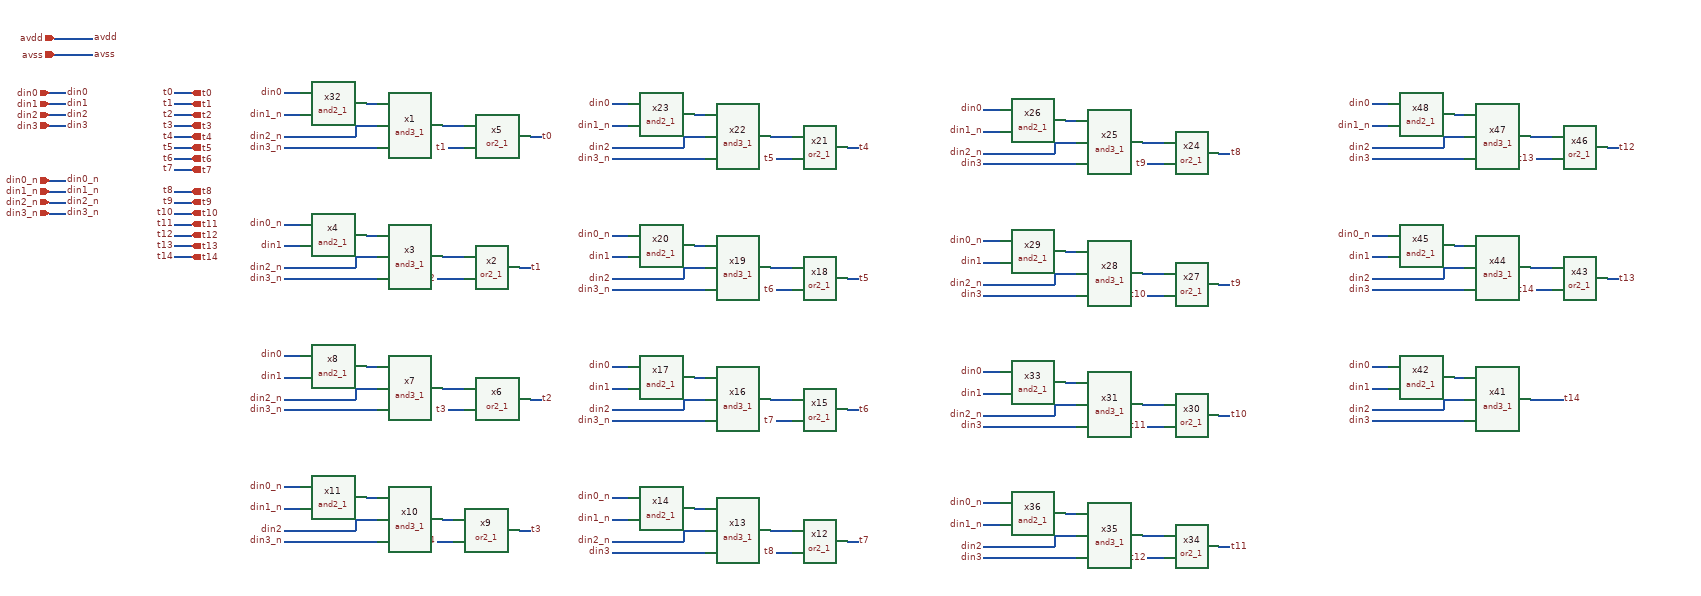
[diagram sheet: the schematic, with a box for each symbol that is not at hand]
v {xschem version=3.4.5 file_version=1.2
}
G {}
K {}
V {}
S {}
E {}
N -50 -70 -20 -70 {
lab=din0}
N -50 -50 -20 -50 {
lab=din1}
N -50 -30 -20 -30 {
lab=din2}
N -50 -10 -20 -10 {
lab=din3}
N -50 90 -20 90 {
lab=din0_n}
N -50 110 -20 110 {
lab=din1_n}
N -50 130 -20 130 {
lab=din2_n}
N -50 150 -20 150 {
lab=din3_n}
N 180 -70 210 -70 {
lab=t0}
N 180 -50 210 -50 {
lab=t1}
N 180 -30 210 -30 {
lab=t2}
N 180 -10 210 -10 {
lab=t3}
N 180 10 210 10 {
lab=t4}
N 180 30 210 30 {
lab=t5}
N 180 50 210 50 {
lab=t6}
N 180 70 210 70 {
lab=t7}
N 180 110 210 110 {
lab=t8}
N 180 130 210 130 {
lab=t9}
N 180 150 210 150 {
lab=t10}
N 180 170 210 170 {
lab=t11}
N 180 190 210 190 {
lab=t12}
N 180 210 210 210 {
lab=t13}
N 180 230 210 230 {
lab=t14}
N -40 -170 30 -170 {
lab=avdd}
N -40 -140 30 -140 {
lab=avss}
N 380 30 410 30 {
lab=din3_n}
N 380 10 410 10 {
lab=din2_n}
N 380 -30 410 -30 {
lab=din1_n}
N 380 -70 410 -70 {
lab=din0}
N 830 10 850 10 {
lab=t0}
N 670 -10 690 -10 {
lab=#net1}
N 680 30 710 30 {
lab=t1}
N 380 270 410 270 {
lab=din3_n}
N 380 250 410 250 {
lab=din2_n}
N 380 210 410 210 {
lab=din1}
N 380 170 410 170 {
lab=din0_n}
N 810 250 830 250 {
lab=t1}
N 660 270 690 270 {
lab=t2}
N 380 510 410 510 {
lab=din3_n}
N 380 490 410 490 {
lab=din2_n}
N 380 450 410 450 {
lab=din1}
N 380 410 410 410 {
lab=din0}
N 830 490 850 490 {
lab=t2}
N 690 470 710 470 {
lab=#net2}
N 680 510 710 510 {
lab=t3}
N 380 750 410 750 {
lab=din3_n}
N 380 730 410 730 {
lab=din2}
N 380 690 410 690 {
lab=din1_n}
N 380 650 410 650 {
lab=din0_n}
N 810 730 830 730 {
lab=t3}
N 670 710 690 710 {
lab=#net3}
N 660 750 690 750 {
lab=t4}
N 980 50 1010 50 {
lab=din3_n}
N 980 30 1010 30 {
lab=din2}
N 980 -10 1010 -10 {
lab=din1_n}
N 980 -50 1010 -50 {
lab=din0}
N 1410 30 1430 30 {
lab=t4}
N 1290 10 1310 10 {
lab=#net4}
N 1280 50 1310 50 {
lab=t5}
N 980 290 1010 290 {
lab=din3_n}
N 980 270 1010 270 {
lab=din2}
N 980 230 1010 230 {
lab=din1}
N 980 190 1010 190 {
lab=din0_n}
N 1410 270 1430 270 {
lab=t5}
N 1290 250 1310 250 {
lab=#net5}
N 1280 290 1310 290 {
lab=t6}
N 980 530 1010 530 {
lab=din3_n}
N 980 510 1010 510 {
lab=din2}
N 980 470 1010 470 {
lab=din1}
N 980 430 1010 430 {
lab=din0}
N 1410 510 1430 510 {
lab=t6}
N 1290 490 1310 490 {
lab=#net6}
N 1280 530 1310 530 {
lab=t7}
N 980 770 1010 770 {
lab=din3}
N 980 750 1010 750 {
lab=din2_n}
N 980 710 1010 710 {
lab=din1_n}
N 980 670 1010 670 {
lab=din0_n}
N 1410 750 1430 750 {
lab=t7}
N 1290 730 1310 730 {
lab=#net7}
N 1280 770 1310 770 {
lab=t8}
N 1660 60 1690 60 {
lab=din3}
N 1660 40 1690 40 {
lab=din2_n}
N 1660 0 1690 0 {
lab=din1_n}
N 1660 -40 1690 -40 {
lab=din0}
N 2090 40 2110 40 {
lab=t8}
N 1970 20 1990 20 {
lab=#net8}
N 1960 60 1990 60 {
lab=t9}
N 1660 300 1690 300 {
lab=din3}
N 1660 280 1690 280 {
lab=din2_n}
N 1660 240 1690 240 {
lab=din1}
N 1660 200 1690 200 {
lab=din0_n}
N 2090 280 2110 280 {
lab=t9}
N 1970 260 1990 260 {
lab=#net9}
N 1960 300 1990 300 {
lab=t10}
N 1660 540 1690 540 {
lab=din3}
N 1660 520 1690 520 {
lab=din2_n}
N 1660 480 1690 480 {
lab=din1}
N 1660 440 1690 440 {
lab=din0}
N 2090 520 2110 520 {
lab=t10}
N 1970 500 1990 500 {
lab=#net10}
N 1960 540 1990 540 {
lab=t11}
N 1660 780 1690 780 {
lab=din3}
N 1660 760 1690 760 {
lab=din2}
N 1660 720 1690 720 {
lab=din1_n}
N 1660 680 1690 680 {
lab=din0_n}
N 2090 760 2110 760 {
lab=t11}
N 1970 740 1990 740 {
lab=#net11}
N 1960 780 1990 780 {
lab=t12}
N 2370 50 2400 50 {
lab=din3}
N 2370 30 2400 30 {
lab=din2}
N 2370 -10 2400 -10 {
lab=din1_n}
N 2370 -50 2400 -50 {
lab=din0}
N 2800 30 2820 30 {
lab=t12}
N 2680 10 2700 10 {
lab=#net12}
N 2670 50 2700 50 {
lab=t13}
N 2370 290 2400 290 {
lab=din3}
N 2370 270 2400 270 {
lab=din2}
N 2370 230 2400 230 {
lab=din1}
N 2370 190 2400 190 {
lab=din0_n}
N 2800 270 2820 270 {
lab=t13}
N 2680 250 2700 250 {
lab=#net13}
N 2670 290 2700 290 {
lab=t14}
N 2370 530 2400 530 {
lab=din3}
N 2370 510 2400 510 {
lab=din2}
N 2370 470 2400 470 {
lab=din1}
N 2370 430 2400 430 {
lab=din0}
N 2700 490 2720 490 {
lab=t14}
N 2680 490 2700 490 {
lab=t14}
N 530 -50 550 -50 {
lab=#net14}
N 510 -10 550 -10 {
lab=din2_n}
N 690 -10 710 -10 {
lab=#net1}
N 510 -10 510 10 {
lab=din2_n}
N 410 10 510 10 {
lab=din2_n}
N 410 30 550 30 {
lab=din3_n}
N 670 230 690 230 {
lab=#net15}
N 530 190 550 190 {
lab=#net16}
N 510 230 550 230 {
lab=din2_n}
N 510 230 510 250 {
lab=din2_n}
N 410 250 510 250 {
lab=din2_n}
N 410 270 550 270 {
lab=din3_n}
N 530 430 550 430 {
lab=#net17}
N 510 470 550 470 {
lab=din2_n}
N 510 470 510 490 {
lab=din2_n}
N 410 490 510 490 {
lab=din2_n}
N 410 510 550 510 {
lab=din3_n}
N 530 670 550 670 {
lab=#net18}
N 510 710 550 710 {
lab=din2}
N 510 710 510 730 {
lab=din2}
N 410 730 510 730 {
lab=din2}
N 410 750 550 750 {
lab=din3_n}
N 1270 730 1290 730 {
lab=#net7}
N 1130 690 1150 690 {
lab=#net19}
N 1110 730 1150 730 {
lab=din2_n}
N 1110 730 1110 750 {
lab=din2_n}
N 1010 750 1110 750 {
lab=din2_n}
N 1010 770 1150 770 {
lab=din3}
N 1270 490 1290 490 {
lab=#net6}
N 1130 450 1150 450 {
lab=#net20}
N 1110 490 1150 490 {
lab=din2}
N 1110 490 1110 510 {
lab=din2}
N 1010 510 1110 510 {
lab=din2}
N 1010 530 1150 530 {
lab=din3_n}
N 1270 250 1290 250 {
lab=#net5}
N 1130 210 1150 210 {
lab=#net21}
N 1110 250 1150 250 {
lab=din2}
N 1110 250 1110 270 {
lab=din2}
N 1010 270 1110 270 {
lab=din2}
N 1010 290 1150 290 {
lab=din3_n}
N 1270 10 1290 10 {
lab=#net4}
N 1130 -30 1150 -30 {
lab=#net22}
N 1110 10 1150 10 {
lab=din2}
N 1110 10 1110 30 {
lab=din2}
N 1010 30 1110 30 {
lab=din2}
N 1010 50 1150 50 {
lab=din3_n}
N 1950 20 1970 20 {
lab=#net8}
N 1810 -20 1830 -20 {
lab=#net23}
N 1790 20 1830 20 {
lab=din2_n}
N 1790 20 1790 40 {
lab=din2_n}
N 1690 40 1790 40 {
lab=din2_n}
N 1690 60 1830 60 {
lab=din3}
N 1950 260 1970 260 {
lab=#net9}
N 1810 220 1830 220 {
lab=#net24}
N 1790 260 1830 260 {
lab=din2_n}
N 1790 260 1790 280 {
lab=din2_n}
N 1690 280 1790 280 {
lab=din2_n}
N 1690 300 1830 300 {
lab=din3}
N 1950 500 1970 500 {
lab=#net10}
N 1810 460 1830 460 {
lab=#net25}
N 1790 500 1830 500 {
lab=din2_n}
N 1790 500 1790 520 {
lab=din2_n}
N 1690 520 1790 520 {
lab=din2_n}
N 1690 540 1830 540 {
lab=din3}
N 1950 740 1970 740 {
lab=#net11}
N 1810 700 1830 700 {
lab=#net26}
N 1790 740 1830 740 {
lab=din2}
N 1790 740 1790 760 {
lab=din2}
N 1690 760 1790 760 {
lab=din2}
N 1690 780 1830 780 {
lab=din3}
N 2660 10 2680 10 {
lab=#net12}
N 2520 -30 2540 -30 {
lab=#net27}
N 2500 10 2540 10 {
lab=din2}
N 2500 10 2500 30 {
lab=din2}
N 2400 30 2500 30 {
lab=din2}
N 2400 50 2540 50 {
lab=din3}
N 2660 250 2680 250 {
lab=#net13}
N 2520 210 2540 210 {
lab=#net28}
N 2500 250 2540 250 {
lab=din2}
N 2500 250 2500 270 {
lab=din2}
N 2400 270 2500 270 {
lab=din2}
N 2400 290 2540 290 {
lab=din3}
N 2660 490 2680 490 {
lab=t14}
N 2520 450 2540 450 {
lab=#net29}
N 2500 490 2540 490 {
lab=din2}
N 2500 490 2500 510 {
lab=din2}
N 2400 510 2500 510 {
lab=din2}
N 2400 530 2540 530 {
lab=din3}
N 670 470 690 470 {
lab=#net2}
N 690 230 710 230 {
lab=#net15}
N 690 270 710 270 {
lab=t2}
C {devices/ipin.sym} -50 -70 0 0 {name=p1 lab=din0}
C {devices/ipin.sym} -50 -50 0 0 {name=p2 lab=din1}
C {devices/ipin.sym} -50 -30 0 0 {name=p3 lab=din2}
C {devices/ipin.sym} -50 -10 0 0 {name=p4 lab=din3}
C {devices/ipin.sym} -50 90 0 0 {name=p7 lab=din0_n}
C {devices/ipin.sym} -50 110 0 0 {name=p8 lab=din1_n}
C {devices/ipin.sym} -50 130 0 0 {name=p9 lab=din2_n}
C {devices/ipin.sym} -50 150 0 0 {name=p10 lab=din3_n}
C {devices/opin.sym} 210 -70 0 0 {name=p13 lab=t0}
C {devices/opin.sym} 210 -50 0 0 {name=p14 lab=t1}
C {devices/opin.sym} 210 -30 0 0 {name=p15 lab=t2}
C {devices/opin.sym} 210 -10 0 0 {name=p16 lab=t3}
C {devices/opin.sym} 210 10 0 0 {name=p17 lab=t4}
C {devices/opin.sym} 210 30 0 0 {name=p18 lab=t5}
C {devices/opin.sym} 210 50 0 0 {name=p19 lab=t6}
C {devices/opin.sym} 210 70 0 0 {name=p20 lab=t7}
C {devices/lab_pin.sym} 180 -70 0 0 {name=p21 sig_type=std_logic lab=t0}
C {devices/lab_pin.sym} 180 -50 0 0 {name=p22 sig_type=std_logic lab=t1}
C {devices/lab_pin.sym} 180 -30 0 0 {name=p23 sig_type=std_logic lab=t2}
C {devices/lab_pin.sym} 180 -10 0 0 {name=p24 sig_type=std_logic lab=t3}
C {devices/lab_pin.sym} 180 10 0 0 {name=p25 sig_type=std_logic lab=t4}
C {devices/lab_pin.sym} 180 30 0 0 {name=p26 sig_type=std_logic lab=t5}
C {devices/lab_pin.sym} 180 50 0 0 {name=p27 sig_type=std_logic lab=t6}
C {devices/lab_pin.sym} 180 70 0 0 {name=p28 sig_type=std_logic lab=t7}
C {devices/lab_pin.sym} -20 -70 0 1 {name=p29 sig_type=std_logic lab=din0}
C {devices/lab_pin.sym} -20 -50 0 1 {name=p30 sig_type=std_logic lab=din1}
C {devices/lab_pin.sym} -20 -30 0 1 {name=p31 sig_type=std_logic lab=din2}
C {devices/lab_pin.sym} -20 -10 0 1 {name=p32 sig_type=std_logic lab=din3}
C {devices/lab_pin.sym} -20 90 0 1 {name=p35 sig_type=std_logic lab=din0_n}
C {devices/lab_pin.sym} -20 110 0 1 {name=p36 sig_type=std_logic lab=din1_n}
C {devices/lab_pin.sym} -20 130 0 1 {name=p37 sig_type=std_logic lab=din2_n}
C {devices/lab_pin.sym} -20 150 0 1 {name=p38 sig_type=std_logic lab=din3_n}
C {devices/opin.sym} 210 110 0 0 {name=p41 lab=t8}
C {devices/opin.sym} 210 130 0 0 {name=p42 lab=t9}
C {devices/opin.sym} 210 150 0 0 {name=p43 lab=t10}
C {devices/opin.sym} 210 170 0 0 {name=p44 lab=t11}
C {devices/opin.sym} 210 190 0 0 {name=p45 lab=t12}
C {devices/opin.sym} 210 210 0 0 {name=p46 lab=t13}
C {devices/opin.sym} 210 230 0 0 {name=p47 lab=t14}
C {devices/lab_pin.sym} 180 110 0 0 {name=p49 sig_type=std_logic lab=t8}
C {devices/lab_pin.sym} 180 130 0 0 {name=p50 sig_type=std_logic lab=t9}
C {devices/lab_pin.sym} 180 150 0 0 {name=p51 sig_type=std_logic lab=t10}
C {devices/lab_pin.sym} 180 170 0 0 {name=p52 sig_type=std_logic lab=t11}
C {devices/lab_pin.sym} 180 190 0 0 {name=p53 sig_type=std_logic lab=t12}
C {devices/lab_pin.sym} 180 210 0 0 {name=p54 sig_type=std_logic lab=t13}
C {devices/lab_pin.sym} 180 230 0 0 {name=p55 sig_type=std_logic lab=t14}
C {devices/lab_pin.sym} 380 -70 0 0 {name=p58 sig_type=std_logic lab=din0}
C {devices/lab_pin.sym} 380 -30 0 0 {name=p59 sig_type=std_logic lab=din1_n}
C {devices/lab_pin.sym} 380 10 0 0 {name=p60 sig_type=std_logic lab=din2_n}
C {devices/lab_pin.sym} 380 30 0 0 {name=p61 sig_type=std_logic lab=din3_n}
C {devices/lab_pin.sym} 380 170 0 0 {name=p65 sig_type=std_logic lab=din0_n}
C {devices/lab_pin.sym} 380 210 0 0 {name=p66 sig_type=std_logic lab=din1}
C {devices/lab_pin.sym} 380 250 0 0 {name=p67 sig_type=std_logic lab=din2_n}
C {devices/lab_pin.sym} 380 270 0 0 {name=p68 sig_type=std_logic lab=din3_n}
C {devices/lab_pin.sym} 380 410 0 0 {name=p72 sig_type=std_logic lab=din0}
C {devices/lab_pin.sym} 380 450 0 0 {name=p73 sig_type=std_logic lab=din1}
C {devices/lab_pin.sym} 380 490 0 0 {name=p74 sig_type=std_logic lab=din2_n}
C {devices/lab_pin.sym} 380 510 0 0 {name=p75 sig_type=std_logic lab=din3_n}
C {devices/lab_pin.sym} 380 650 0 0 {name=p79 sig_type=std_logic lab=din0_n}
C {devices/lab_pin.sym} 380 690 0 0 {name=p80 sig_type=std_logic lab=din1_n}
C {devices/lab_pin.sym} 380 730 0 0 {name=p81 sig_type=std_logic lab=din2}
C {devices/lab_pin.sym} 380 750 0 0 {name=p82 sig_type=std_logic lab=din3_n}
C {devices/lab_pin.sym} 980 -50 0 0 {name=p86 sig_type=std_logic lab=din0}
C {devices/lab_pin.sym} 980 -10 0 0 {name=p87 sig_type=std_logic lab=din1_n}
C {devices/lab_pin.sym} 980 30 0 0 {name=p88 sig_type=std_logic lab=din2}
C {devices/lab_pin.sym} 980 50 0 0 {name=p89 sig_type=std_logic lab=din3_n}
C {devices/lab_pin.sym} 980 190 0 0 {name=p93 sig_type=std_logic lab=din0_n}
C {devices/lab_pin.sym} 980 230 0 0 {name=p94 sig_type=std_logic lab=din1}
C {devices/lab_pin.sym} 980 270 0 0 {name=p95 sig_type=std_logic lab=din2}
C {devices/lab_pin.sym} 980 290 0 0 {name=p96 sig_type=std_logic lab=din3_n}
C {devices/lab_pin.sym} 980 430 0 0 {name=p100 sig_type=std_logic lab=din0}
C {devices/lab_pin.sym} 980 470 0 0 {name=p101 sig_type=std_logic lab=din1}
C {devices/lab_pin.sym} 980 510 0 0 {name=p102 sig_type=std_logic lab=din2}
C {devices/lab_pin.sym} 980 530 0 0 {name=p103 sig_type=std_logic lab=din3_n}
C {devices/lab_pin.sym} 980 670 0 0 {name=p107 sig_type=std_logic lab=din0_n}
C {devices/lab_pin.sym} 980 710 0 0 {name=p108 sig_type=std_logic lab=din1_n}
C {devices/lab_pin.sym} 980 750 0 0 {name=p109 sig_type=std_logic lab=din2_n}
C {devices/lab_pin.sym} 980 770 0 0 {name=p110 sig_type=std_logic lab=din3}
C {devices/lab_pin.sym} 1660 -40 0 0 {name=p114 sig_type=std_logic lab=din0}
C {devices/lab_pin.sym} 1660 0 0 0 {name=p115 sig_type=std_logic lab=din1_n}
C {devices/lab_pin.sym} 1660 40 0 0 {name=p116 sig_type=std_logic lab=din2_n}
C {devices/lab_pin.sym} 1660 60 0 0 {name=p117 sig_type=std_logic lab=din3}
C {devices/lab_pin.sym} 1660 200 0 0 {name=p121 sig_type=std_logic lab=din0_n}
C {devices/lab_pin.sym} 1660 240 0 0 {name=p122 sig_type=std_logic lab=din1}
C {devices/lab_pin.sym} 1660 280 0 0 {name=p123 sig_type=std_logic lab=din2_n}
C {devices/lab_pin.sym} 1660 300 0 0 {name=p124 sig_type=std_logic lab=din3}
C {devices/lab_pin.sym} 1660 440 0 0 {name=p128 sig_type=std_logic lab=din0}
C {devices/lab_pin.sym} 1660 480 0 0 {name=p129 sig_type=std_logic lab=din1}
C {devices/lab_pin.sym} 1660 520 0 0 {name=p130 sig_type=std_logic lab=din2_n}
C {devices/lab_pin.sym} 1660 540 0 0 {name=p131 sig_type=std_logic lab=din3}
C {devices/lab_pin.sym} 1660 680 0 0 {name=p135 sig_type=std_logic lab=din0_n}
C {devices/lab_pin.sym} 1660 720 0 0 {name=p136 sig_type=std_logic lab=din1_n}
C {devices/lab_pin.sym} 1660 760 0 0 {name=p137 sig_type=std_logic lab=din2}
C {devices/lab_pin.sym} 1660 780 0 0 {name=p138 sig_type=std_logic lab=din3}
C {devices/lab_pin.sym} 2370 -50 0 0 {name=p142 sig_type=std_logic lab=din0}
C {devices/lab_pin.sym} 2370 -10 0 0 {name=p143 sig_type=std_logic lab=din1_n}
C {devices/lab_pin.sym} 2370 30 0 0 {name=p144 sig_type=std_logic lab=din2}
C {devices/lab_pin.sym} 2370 50 0 0 {name=p145 sig_type=std_logic lab=din3}
C {devices/lab_pin.sym} 2370 190 0 0 {name=p149 sig_type=std_logic lab=din0_n}
C {devices/lab_pin.sym} 2370 230 0 0 {name=p150 sig_type=std_logic lab=din1}
C {devices/lab_pin.sym} 2370 270 0 0 {name=p151 sig_type=std_logic lab=din2}
C {devices/lab_pin.sym} 2370 290 0 0 {name=p152 sig_type=std_logic lab=din3}
C {devices/lab_pin.sym} 2370 430 0 0 {name=p156 sig_type=std_logic lab=din0}
C {devices/lab_pin.sym} 2370 470 0 0 {name=p157 sig_type=std_logic lab=din1}
C {devices/lab_pin.sym} 2370 510 0 0 {name=p158 sig_type=std_logic lab=din2}
C {devices/lab_pin.sym} 2370 530 0 0 {name=p159 sig_type=std_logic lab=din3}
C {devices/ipin.sym} -40 -170 0 0 {name=p169 lab=avdd}
C {devices/ipin.sym} -40 -140 0 0 {name=p170 lab=avss}
C {devices/lab_pin.sym} 30 -170 0 1 {name=p171 sig_type=std_logic lab=avdd}
C {devices/lab_pin.sym} 30 -140 0 1 {name=p172 sig_type=std_logic lab=avss}
C {sky130_stdcells/or2_1.sym} 770 10 0 0 {name=x5 VGND=avss VNB=avss VPB=avdd VPWR=avdd prefix=sky130_fd_sc_hvl__ }
C {devices/lab_pin.sym} 850 10 0 1 {name=p85 sig_type=std_logic lab=t0}
C {devices/lab_pin.sym} 680 30 0 0 {name=p57 sig_type=std_logic lab=t1}
C {devices/lab_pin.sym} 830 250 0 1 {name=p62 sig_type=std_logic lab=t1}
C {devices/lab_pin.sym} 660 270 0 0 {name=p63 sig_type=std_logic lab=t2}
C {devices/lab_pin.sym} 850 490 0 1 {name=p64 sig_type=std_logic lab=t2}
C {devices/lab_pin.sym} 680 510 0 0 {name=p71 sig_type=std_logic lab=t3}
C {devices/lab_pin.sym} 830 730 0 1 {name=p78 sig_type=std_logic lab=t3}
C {devices/lab_pin.sym} 660 750 0 0 {name=p92 sig_type=std_logic lab=t4}
C {devices/lab_pin.sym} 1430 30 0 1 {name=p69 sig_type=std_logic lab=t4}
C {devices/lab_pin.sym} 1280 50 0 0 {name=p70 sig_type=std_logic lab=t5}
C {devices/lab_pin.sym} 1430 270 0 1 {name=p76 sig_type=std_logic lab=t5}
C {devices/lab_pin.sym} 1280 290 0 0 {name=p77 sig_type=std_logic lab=t6}
C {devices/lab_pin.sym} 1430 510 0 1 {name=p83 sig_type=std_logic lab=t6}
C {devices/lab_pin.sym} 1280 530 0 0 {name=p84 sig_type=std_logic lab=t7}
C {devices/lab_pin.sym} 1430 750 0 1 {name=p99 sig_type=std_logic lab=t7}
C {devices/lab_pin.sym} 1280 770 0 0 {name=p106 sig_type=std_logic lab=t8}
C {devices/lab_pin.sym} 2110 40 0 1 {name=p113 sig_type=std_logic lab=t8}
C {devices/lab_pin.sym} 1960 60 0 0 {name=p120 sig_type=std_logic lab=t9}
C {devices/lab_pin.sym} 2110 280 0 1 {name=p127 sig_type=std_logic lab=t9}
C {devices/lab_pin.sym} 1960 300 0 0 {name=p134 sig_type=std_logic lab=t10}
C {devices/lab_pin.sym} 2110 520 0 1 {name=p141 sig_type=std_logic lab=t10}
C {devices/lab_pin.sym} 1960 540 0 0 {name=p148 sig_type=std_logic lab=t11}
C {devices/lab_pin.sym} 2110 760 0 1 {name=p155 sig_type=std_logic lab=t11}
C {devices/lab_pin.sym} 1960 780 0 0 {name=p162 sig_type=std_logic lab=t12}
C {devices/lab_pin.sym} 2820 30 0 1 {name=p173 sig_type=std_logic lab=t12}
C {devices/lab_pin.sym} 2670 50 0 0 {name=p174 sig_type=std_logic lab=t13}
C {devices/lab_pin.sym} 2820 270 0 1 {name=p175 sig_type=std_logic lab=t13}
C {devices/lab_pin.sym} 2670 290 0 0 {name=p176 sig_type=std_logic lab=t14}
C {devices/lab_pin.sym} 2720 490 0 1 {name=p177 sig_type=std_logic lab=t14}
C {sky130_stdcells/and3_1.sym} 610 -10 0 0 {name=x1 VGND=avss VNB=avss VPB=avdd VPWR=avdd prefix=sky130_fd_sc_hvl__ }
C {sky130_stdcells/and2_1.sym} 470 -50 0 0 {name=x32 VGND=avss VNB=avss VPB=avdd VPWR=avdd prefix=sky130_fd_sc_hvl__ }
C {sky130_stdcells/or2_1.sym} 770 250 0 0 {name=x2 VGND=avss VNB=avss VPB=avdd VPWR=avdd prefix=sky130_fd_sc_hvl__ }
C {sky130_stdcells/and3_1.sym} 610 230 0 0 {name=x3 VGND=avss VNB=avss VPB=avdd VPWR=avdd prefix=sky130_fd_sc_hvl__ }
C {sky130_stdcells/and2_1.sym} 470 190 0 0 {name=x4 VGND=avss VNB=avss VPB=avdd VPWR=avdd prefix=sky130_fd_sc_hvl__ }
C {sky130_stdcells/or2_1.sym} 770 490 0 0 {name=x6 VGND=avss VNB=avss VPB=avdd VPWR=avdd prefix=sky130_fd_sc_hvl__ }
C {sky130_stdcells/and3_1.sym} 610 470 0 0 {name=x7 VGND=avss VNB=avss VPB=avdd VPWR=avdd prefix=sky130_fd_sc_hvl__ }
C {sky130_stdcells/and2_1.sym} 470 430 0 0 {name=x8 VGND=avss VNB=avss VPB=avdd VPWR=avdd prefix=sky130_fd_sc_hvl__ }
C {sky130_stdcells/or2_1.sym} 750 730 0 0 {name=x9 VGND=avss VNB=avss VPB=avdd VPWR=avdd prefix=sky130_fd_sc_hvl__ }
C {sky130_stdcells/and3_1.sym} 610 710 0 0 {name=x10 VGND=avss VNB=avss VPB=avdd VPWR=avdd prefix=sky130_fd_sc_hvl__ }
C {sky130_stdcells/and2_1.sym} 470 670 0 0 {name=x11 VGND=avss VNB=avss VPB=avdd VPWR=avdd prefix=sky130_fd_sc_hvl__ }
C {sky130_stdcells/or2_1.sym} 1350 750 0 0 {name=x12 VGND=avss VNB=avss VPB=avdd VPWR=avdd prefix=sky130_fd_sc_hvl__ }
C {sky130_stdcells/and3_1.sym} 1210 730 0 0 {name=x13 VGND=avss VNB=avss VPB=avdd VPWR=avdd prefix=sky130_fd_sc_hvl__ }
C {sky130_stdcells/and2_1.sym} 1070 690 0 0 {name=x14 VGND=avss VNB=avss VPB=avdd VPWR=avdd prefix=sky130_fd_sc_hvl__ }
C {sky130_stdcells/or2_1.sym} 1350 510 0 0 {name=x15 VGND=avss VNB=avss VPB=avdd VPWR=avdd prefix=sky130_fd_sc_hvl__ }
C {sky130_stdcells/and3_1.sym} 1210 490 0 0 {name=x16 VGND=avss VNB=avss VPB=avdd VPWR=avdd prefix=sky130_fd_sc_hvl__ }
C {sky130_stdcells/and2_1.sym} 1070 450 0 0 {name=x17 VGND=avss VNB=avss VPB=avdd VPWR=avdd prefix=sky130_fd_sc_hvl__ }
C {sky130_stdcells/or2_1.sym} 1350 270 0 0 {name=x18 VGND=avss VNB=avss VPB=avdd VPWR=avdd prefix=sky130_fd_sc_hvl__ }
C {sky130_stdcells/and3_1.sym} 1210 250 0 0 {name=x19 VGND=avss VNB=avss VPB=avdd VPWR=avdd prefix=sky130_fd_sc_hvl__ }
C {sky130_stdcells/and2_1.sym} 1070 210 0 0 {name=x20 VGND=avss VNB=avss VPB=avdd VPWR=avdd prefix=sky130_fd_sc_hvl__ }
C {sky130_stdcells/or2_1.sym} 1350 30 0 0 {name=x21 VGND=avss VNB=avss VPB=avdd VPWR=avdd prefix=sky130_fd_sc_hvl__ }
C {sky130_stdcells/and3_1.sym} 1210 10 0 0 {name=x22 VGND=avss VNB=avss VPB=avdd VPWR=avdd prefix=sky130_fd_sc_hvl__ }
C {sky130_stdcells/and2_1.sym} 1070 -30 0 0 {name=x23 VGND=avss VNB=avss VPB=avdd VPWR=avdd prefix=sky130_fd_sc_hvl__ }
C {sky130_stdcells/or2_1.sym} 2030 40 0 0 {name=x24 VGND=avss VNB=avss VPB=avdd VPWR=avdd prefix=sky130_fd_sc_hvl__ }
C {sky130_stdcells/and3_1.sym} 1890 20 0 0 {name=x25 VGND=avss VNB=avss VPB=avdd VPWR=avdd prefix=sky130_fd_sc_hvl__ }
C {sky130_stdcells/and2_1.sym} 1750 -20 0 0 {name=x26 VGND=avss VNB=avss VPB=avdd VPWR=avdd prefix=sky130_fd_sc_hvl__ }
C {sky130_stdcells/or2_1.sym} 2030 280 0 0 {name=x27 VGND=avss VNB=avss VPB=avdd VPWR=avdd prefix=sky130_fd_sc_hvl__ }
C {sky130_stdcells/and3_1.sym} 1890 260 0 0 {name=x28 VGND=avss VNB=avss VPB=avdd VPWR=avdd prefix=sky130_fd_sc_hvl__ }
C {sky130_stdcells/and2_1.sym} 1750 220 0 0 {name=x29 VGND=avss VNB=avss VPB=avdd VPWR=avdd prefix=sky130_fd_sc_hvl__ }
C {sky130_stdcells/or2_1.sym} 2030 520 0 0 {name=x30 VGND=avss VNB=avss VPB=avdd VPWR=avdd prefix=sky130_fd_sc_hvl__ }
C {sky130_stdcells/and3_1.sym} 1890 500 0 0 {name=x31 VGND=avss VNB=avss VPB=avdd VPWR=avdd prefix=sky130_fd_sc_hvl__ }
C {sky130_stdcells/and2_1.sym} 1750 460 0 0 {name=x33 VGND=avss VNB=avss VPB=avdd VPWR=avdd prefix=sky130_fd_sc_hvl__ }
C {sky130_stdcells/or2_1.sym} 2030 760 0 0 {name=x34 VGND=avss VNB=avss VPB=avdd VPWR=avdd prefix=sky130_fd_sc_hvl__ }
C {sky130_stdcells/and3_1.sym} 1890 740 0 0 {name=x35 VGND=avss VNB=avss VPB=avdd VPWR=avdd prefix=sky130_fd_sc_hvl__ }
C {sky130_stdcells/and2_1.sym} 1750 700 0 0 {name=x36 VGND=avss VNB=avss VPB=avdd VPWR=avdd prefix=sky130_fd_sc_hvl__ }
C {sky130_stdcells/and3_1.sym} 2600 490 0 0 {name=x41 VGND=avss VNB=avss VPB=avdd VPWR=avdd prefix=sky130_fd_sc_hvl__ }
C {sky130_stdcells/and2_1.sym} 2460 450 0 0 {name=x42 VGND=avss VNB=avss VPB=avdd VPWR=avdd prefix=sky130_fd_sc_hvl__ }
C {sky130_stdcells/or2_1.sym} 2740 270 0 0 {name=x43 VGND=avss VNB=avss VPB=avdd VPWR=avdd prefix=sky130_fd_sc_hvl__ }
C {sky130_stdcells/and3_1.sym} 2600 250 0 0 {name=x44 VGND=avss VNB=avss VPB=avdd VPWR=avdd prefix=sky130_fd_sc_hvl__ }
C {sky130_stdcells/and2_1.sym} 2460 210 0 0 {name=x45 VGND=avss VNB=avss VPB=avdd VPWR=avdd prefix=sky130_fd_sc_hvl__ }
C {sky130_stdcells/or2_1.sym} 2740 30 0 0 {name=x46 VGND=avss VNB=avss VPB=avdd VPWR=avdd prefix=sky130_fd_sc_hvl__ }
C {sky130_stdcells/and3_1.sym} 2600 10 0 0 {name=x47 VGND=avss VNB=avss VPB=avdd VPWR=avdd prefix=sky130_fd_sc_hvl__ }
C {sky130_stdcells/and2_1.sym} 2460 -30 0 0 {name=x48 VGND=avss VNB=avss VPB=avdd VPWR=avdd prefix=sky130_fd_sc_hvl__ }
